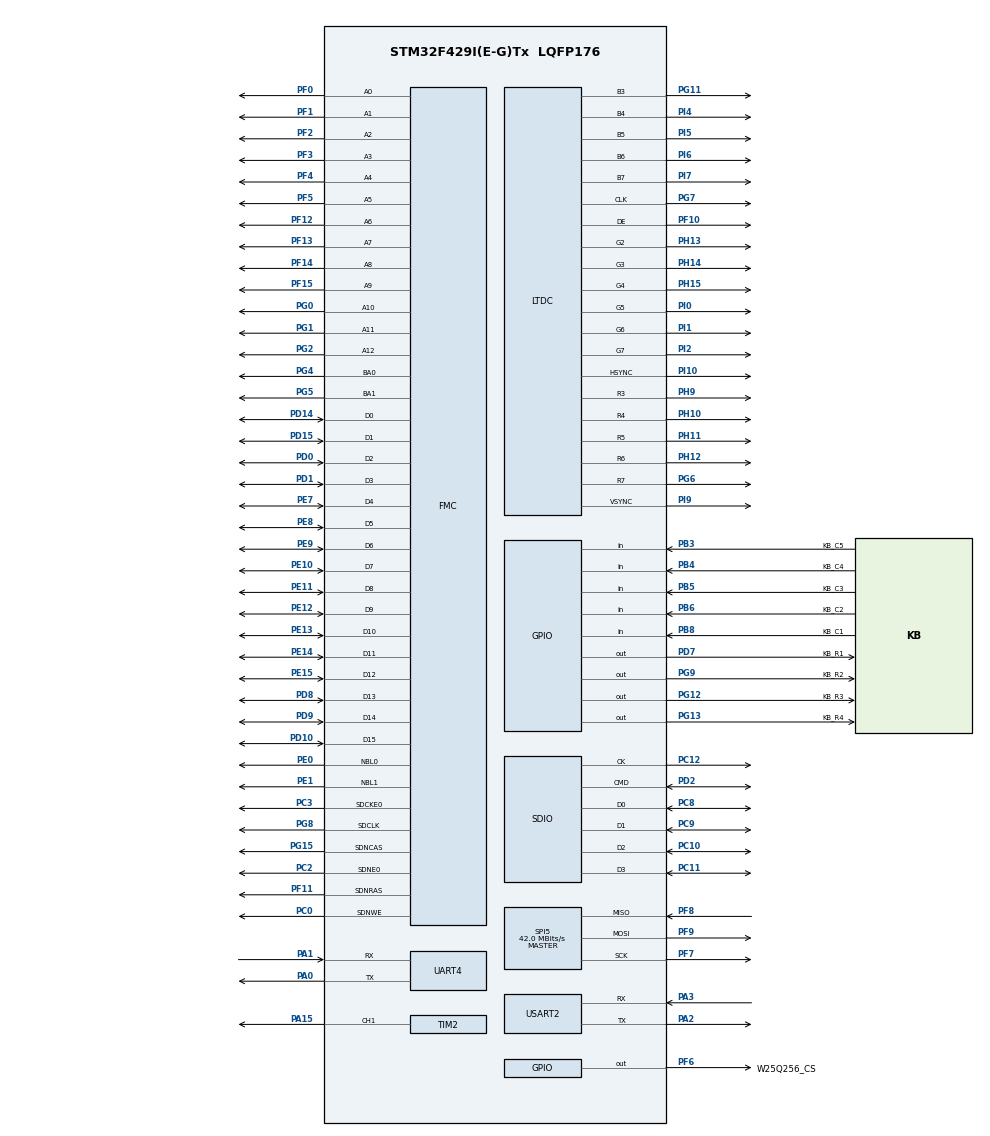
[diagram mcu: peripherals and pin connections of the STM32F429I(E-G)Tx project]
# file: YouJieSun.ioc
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DMA2D.ColorMode=DMA2D_OUTPUT_RGB565
Dma.Request0=UART4_TX
Dma.Request1=UART4_RX
Dma.Request2=USART2_RX
Dma.Request3=USART2_TX
Dma.Request4=SPI5_RX
Dma.Request5=SPI5_TX
Dma.Request6=SDIO_RX
Dma.Request7=SDIO_TX
Dma.SDIO_RX.6.Direction=DMA_PERIPH_TO_MEMORY
Dma.SDIO_RX.6.FIFOMode=DMA_FIFOMODE_ENABLE
Dma.SDIO_RX.6.FIFOThreshold=DMA_FIFO_THRESHOLD_FULL
Dma.SDIO_RX.6.Instance=DMA2_Stream6
Dma.SDIO_RX.6.MemBurst=DMA_MBURST_INC4
Dma.SDIO_RX.6.MemDataAlignment=DMA_MDATAALIGN_WORD
Dma.SDIO_RX.6.MemInc=DMA_MINC_ENABLE
Dma.SDIO_RX.6.Mode=DMA_PFCTRL
Dma.SDIO_RX.6.PeriphBurst=DMA_PBURST_INC4
Dma.SDIO_RX.6.PeriphDataAlignment=DMA_PDATAALIGN_WORD
Dma.SDIO_RX.6.PeriphInc=DMA_PINC_DISABLE
Dma.SDIO_RX.6.Priority=DMA_PRIORITY_LOW
Dma.SDIO_TX.7.Direction=DMA_MEMORY_TO_PERIPH
Dma.SDIO_TX.7.FIFOMode=DMA_FIFOMODE_ENABLE
Dma.SDIO_TX.7.FIFOThreshold=DMA_FIFO_THRESHOLD_FULL
Dma.SDIO_TX.7.Instance=DMA2_Stream3
Dma.SDIO_TX.7.MemBurst=DMA_MBURST_INC4
Dma.SDIO_TX.7.MemDataAlignment=DMA_MDATAALIGN_WORD
Dma.SDIO_TX.7.MemInc=DMA_MINC_ENABLE
Dma.SDIO_TX.7.Mode=DMA_PFCTRL
Dma.SDIO_TX.7.PeriphBurst=DMA_PBURST_INC4
Dma.SDIO_TX.7.PeriphDataAlignment=DMA_PDATAALIGN_WORD
Dma.SDIO_TX.7.PeriphInc=DMA_PINC_DISABLE
Dma.SDIO_TX.7.Priority=DMA_PRIORITY_LOW
Dma.SPI5_RX.4.Direction=DMA_PERIPH_TO_MEMORY
Dma.SPI5_RX.4.FIFOMode=DMA_FIFOMODE_DISABLE
Dma.SPI5_RX.4.Instance=DMA2_Stream5
Dma.SPI5_RX.4.MemDataAlignment=DMA_MDATAALIGN_BYTE
Dma.SPI5_RX.4.MemInc=DMA_MINC_ENABLE
Dma.SPI5_RX.4.Mode=DMA_NORMAL
Dma.SPI5_RX.4.PeriphDataAlignment=DMA_PDATAALIGN_BYTE
Dma.SPI5_RX.4.PeriphInc=DMA_PINC_DISABLE
Dma.SPI5_RX.4.Priority=DMA_PRIORITY_LOW
Dma.SPI5_TX.5.Direction=DMA_MEMORY_TO_PERIPH
Dma.SPI5_TX.5.FIFOMode=DMA_FIFOMODE_DISABLE
Dma.SPI5_TX.5.Instance=DMA2_Stream4
Dma.SPI5_TX.5.MemDataAlignment=DMA_MDATAALIGN_BYTE
Dma.SPI5_TX.5.MemInc=DMA_MINC_ENABLE
Dma.SPI5_TX.5.Mode=DMA_NORMAL
Dma.SPI5_TX.5.PeriphDataAlignment=DMA_PDATAALIGN_BYTE
Dma.SPI5_TX.5.PeriphInc=DMA_PINC_DISABLE
Dma.SPI5_TX.5.Priority=DMA_PRIORITY_LOW
Dma.UART4_RX.1.Direction=DMA_PERIPH_TO_MEMORY
Dma.UART4_RX.1.FIFOMode=DMA_FIFOMODE_DISABLE
Dma.UART4_RX.1.Instance=DMA1_Stream2
Dma.UART4_RX.1.MemDataAlignment=DMA_MDATAALIGN_BYTE
Dma.UART4_RX.1.MemInc=DMA_MINC_ENABLE
Dma.UART4_RX.1.Mode=DMA_NORMAL
Dma.UART4_RX.1.PeriphDataAlignment=DMA_PDATAALIGN_BYTE
Dma.UART4_RX.1.PeriphInc=DMA_PINC_DISABLE
Dma.UART4_RX.1.Priority=DMA_PRIORITY_LOW
Dma.UART4_TX.0.Direction=DMA_MEMORY_TO_PERIPH
Dma.UART4_TX.0.FIFOMode=DMA_FIFOMODE_DISABLE
Dma.UART4_TX.0.Instance=DMA1_Stream4
Dma.UART4_TX.0.MemDataAlignment=DMA_MDATAALIGN_BYTE
Dma.UART4_TX.0.MemInc=DMA_MINC_ENABLE
Dma.UART4_TX.0.Mode=DMA_NORMAL
Dma.UART4_TX.0.PeriphDataAlignment=DMA_PDATAALIGN_BYTE
Dma.UART4_TX.0.PeriphInc=DMA_PINC_DISABLE
Dma.UART4_TX.0.Priority=DMA_PRIORITY_LOW
Dma.USART2_RX.2.Direction=DMA_PERIPH_TO_MEMORY
Dma.USART2_RX.2.FIFOMode=DMA_FIFOMODE_DISABLE
Dma.USART2_RX.2.Instance=DMA1_Stream5
Dma.USART2_RX.2.MemDataAlignment=DMA_MDATAALIGN_BYTE
Dma.USART2_RX.2.MemInc=DMA_MINC_ENABLE
Dma.USART2_RX.2.Mode=DMA_NORMAL
Dma.USART2_RX.2.PeriphDataAlignment=DMA_PDATAALIGN_BYTE
Dma.USART2_RX.2.PeriphInc=DMA_PINC_DISABLE
Dma.USART2_RX.2.Priority=DMA_PRIORITY_LOW
Dma.USART2_TX.3.Direction=DMA_MEMORY_TO_PERIPH
Dma.USART2_TX.3.FIFOMode=DMA_FIFOMODE_DISABLE
Dma.USART2_TX.3.Instance=DMA1_Stream6
Dma.USART2_TX.3.MemDataAlignment=DMA_MDATAALIGN_BYTE
Dma.USART2_TX.3.MemInc=DMA_MINC_ENABLE
Dma.USART2_TX.3.Mode=DMA_NORMAL
Dma.USART2_TX.3.PeriphDataAlignment=DMA_PDATAALIGN_BYTE
Dma.USART2_TX.3.PeriphInc=DMA_PINC_DISABLE
Dma.USART2_TX.3.Priority=DMA_PRIORITY_LOW
FATFS._CODE_PAGE=437
FATFS._USE_LFN=3
FATFS._USE_MUTEX=1
FMC.CASLatency1=FMC_SDRAM_CAS_LATENCY_3
FMC.ColumnBitsNumber1=FMC_SDRAM_COLUMN_BITS_NUM_9
FMC.ExitSelfRefreshDelay1=7
FMC.LoadToActiveDelay1=2
FMC.RCDDelay1=2
FMC.RPDelay1=2
FMC.RPDelay2=2
FMC.ReadBurst1=FMC_SDRAM_RBURST_ENABLE
FMC.ReadBurst2=FMC_SDRAM_RBURST_ENABLE
FMC.ReadPipeDelay1=FMC_SDRAM_RPIPE_DELAY_1
FMC.ReadPipeDelay2=FMC_SDRAM_RPIPE_DELAY_1
FMC.RowCycleDelay1=6
FMC.RowCycleDelay2=6
FMC.SDClockPeriod1=FMC_SDRAM_CLOCK_PERIOD_2
FMC.SDClockPeriod2=FMC_SDRAM_CLOCK_PERIOD_2
FMC.SelfRefreshTime1=6
FMC.WriteRecoveryTime1=4
FREERTOS.BinarySemaphores01=ScreenFlushSemaphore,Dynamic,NULL,Depleted
FREERTOS.Tasks01=UITask,24,2048,StartUITask,As weak,NULL,Dynamic,NULL,NULL;KeyScanTask,25,128,StartKeyScanTask,As weak,NULL,Dynamic,NULL,NULL
FREERTOS.configCHECK_FOR_STACK_OVERFLOW=2
FREERTOS.configGENERATE_RUN_TIME_STATS=1
FREERTOS.configRECORD_STACK_HIGH_ADDRESS=1
FREERTOS.configTOTAL_HEAP_SIZE=32768
FREERTOS.configUSE_MALLOC_FAILED_HOOK=1
FREERTOS.configUSE_TASK_NOTIFICATIONS=1
FREERTOS.configUSE_TICK_HOOK=1
LTDC.ActiveW=800
LTDC.Alpha_L0=255
LTDC.FBStartAdress_L0=0xC0000000
LTDC.HBP=8
LTDC.HFP=8
LTDC.HSync=4
LTDC.ImageHeight_L0=480
LTDC.ImageWidth_L0=800
LTDC.Layers=0
LTDC.PixelFormat_L0=LTDC_PIXEL_FORMAT_RGB565
LTDC.VBP=8
LTDC.VFP=8
LTDC.VSync=2
LTDC.WindowX1_L0=800
LTDC.WindowY1_L0=480
Mcu.Family=STM32F4
Mcu.Name=STM32F429I(E-G)Tx
Mcu.Package=LQFP176
NVIC.DMA1_Stream2_IRQn=true\:5\:0\:false\:false\:true\:true\:false\:true\:true
NVIC.DMA1_Stream4_IRQn=true\:5\:0\:false\:false\:true\:true\:false\:true\:true
NVIC.DMA1_Stream5_IRQn=true\:5\:0\:false\:false\:true\:true\:false\:true\:true
NVIC.DMA1_Stream6_IRQn=true\:5\:0\:false\:false\:true\:true\:false\:true\:true
NVIC.DMA2D_IRQn=true\:7\:0\:true\:false\:true\:true\:true\:true\:true
NVIC.DMA2_Stream3_IRQn=true\:7\:0\:true\:false\:true\:true\:false\:true\:true
NVIC.DMA2_Stream4_IRQn=true\:5\:0\:false\:false\:true\:true\:false\:true\:true
NVIC.DMA2_Stream5_IRQn=true\:5\:0\:false\:false\:true\:false\:false\:true\:true
NVIC.DMA2_Stream6_IRQn=true\:7\:0\:true\:false\:true\:true\:false\:true\:true
NVIC.PriorityGroup=NVIC_PRIORITYGROUP_4
NVIC.SDIO_IRQn=true\:6\:0\:true\:false\:true\:true\:true\:true\:true
NVIC.SPI5_IRQn=true\:5\:0\:false\:false\:true\:true\:true\:true\:true
NVIC.TIM6_DAC_IRQn=true\:15\:0\:false\:false\:true\:false\:false\:true\:true
NVIC.TimeBase=TIM6_DAC_IRQn
NVIC.TimeBaseIP=TIM6
NVIC.UART4_IRQn=true\:6\:0\:true\:false\:true\:true\:false\:true\:true
NVIC.USART2_IRQn=true\:5\:0\:true\:false\:true\:true\:true\:true\:true
PA0/WKUP.Mode=Asynchronous
PA0/WKUP.Signal=UART4_TX
PA1.Mode=Asynchronous
PA1.Signal=UART4_RX
PA13.Mode=Serial_Wire
PA13.Signal=SYS_JTMS-SWDIO
PA14.Mode=Serial_Wire
PA14.Signal=SYS_JTCK-SWCLK
PA15.Signal=S_TIM2_CH1_ETR
PA2.Mode=Asynchronous
PA2.Signal=USART2_TX
PA3.Mode=Asynchronous
PA3.Signal=USART2_RX
PB3.GPIO_Label=KB_C5
PB3.GPIO_PuPd=GPIO_PULLUP
PB3.Signal=GPIO_Input
PB4.GPIO_Label=KB_C4
PB4.GPIO_PuPd=GPIO_PULLUP
PB4.Signal=GPIO_Input
PB5.GPIO_Label=KB_C3
PB5.GPIO_PuPd=GPIO_PULLUP
PB5.Signal=GPIO_Input
PB6.GPIO_Label=KB_C2
PB6.GPIO_PuPd=GPIO_PULLUP
PB6.Signal=GPIO_Input
PB8.GPIO_Label=KB_C1
PB8.GPIO_PuPd=GPIO_PULLUP
PB8.Signal=GPIO_Input
PC0.Signal=FMC_SDNWE
PC10.Mode=SD_4_bits_Wide_bus
PC10.Signal=SDIO_D2
PC11.Mode=SD_4_bits_Wide_bus
PC11.Signal=SDIO_D3
PC12.Mode=SD_4_bits_Wide_bus
PC12.Signal=SDIO_CK
PC14/OSC32_IN.Mode=LSE-External-Oscillator
PC14/OSC32_IN.Signal=RCC_OSC32_IN
PC15/OSC32_OUT.Mode=LSE-External-Oscillator
PC15/OSC32_OUT.Signal=RCC_OSC32_OUT
PC2.Mode=SdramChipSelect1_1
PC2.Signal=FMC_SDNE0
PC3.Mode=SdramChipSelect1_1
PC3.Signal=FMC_SDCKE0
PC8.Mode=SD_4_bits_Wide_bus
PC8.Signal=SDIO_D0
PC9.Mode=SD_4_bits_Wide_bus
PC9.Signal=SDIO_D1
PD0.Signal=FMC_D2_DA2
PD1.Signal=FMC_D3_DA3
PD10.Signal=FMC_D15_DA15
PD14.Signal=FMC_D0_DA0
PD15.Signal=FMC_D1_DA1
PD2.Mode=SD_4_bits_Wide_bus
PD2.Signal=SDIO_CMD
PD7.GPIO_Label=KB_R1
PD7.GPIO_Speed=GPIO_SPEED_FREQ_VERY_HIGH
PD7.PinState=GPIO_PIN_SET
PD7.Signal=GPIO_Output
PD8.Signal=FMC_D13_DA13
PD9.Signal=FMC_D14_DA14
PE0.Signal=FMC_NBL0
PE1.Signal=FMC_NBL1
PE10.Signal=FMC_D7_DA7
PE11.Signal=FMC_D8_DA8
PE12.Signal=FMC_D9_DA9
PE13.Signal=FMC_D10_DA10
PE14.Signal=FMC_D11_DA11
PE15.Signal=FMC_D12_DA12
PE7.Signal=FMC_D4_DA4
PE8.Signal=FMC_D5_DA5
PE9.Signal=FMC_D6_DA6
PF0.Signal=FMC_A0
PF1.Signal=FMC_A1
PF10.GPIO_Speed=GPIO_SPEED_FREQ_VERY_HIGH
PF10.Mode=RGB565
PF10.Signal=LTDC_DE
PF11.Signal=FMC_SDNRAS
PF12.Signal=FMC_A6
PF13.Signal=FMC_A7
PF14.Signal=FMC_A8
PF15.Signal=FMC_A9
PF2.Signal=FMC_A2
PF3.Signal=FMC_A3
PF4.Signal=FMC_A4
PF5.Signal=FMC_A5
PF6.GPIO_Label=W25Q256_CS
PF6.GPIO_Speed=GPIO_SPEED_FREQ_VERY_HIGH
PF6.PinState=GPIO_PIN_SET
PF6.Signal=GPIO_Output
PF7.Mode=Full_Duplex_Master
PF7.Signal=SPI5_SCK
PF8.Mode=Full_Duplex_Master
PF8.Signal=SPI5_MISO
PF9.Mode=Full_Duplex_Master
PF9.Signal=SPI5_MOSI
PG0.Signal=FMC_A10
PG1.Signal=FMC_A11
PG11.GPIO_Speed=GPIO_SPEED_FREQ_VERY_HIGH
PG11.Mode=RGB565
PG11.Signal=LTDC_B3
PG12.GPIO_Label=KB_R3
PG12.GPIO_Speed=GPIO_SPEED_FREQ_VERY_HIGH
PG12.PinState=GPIO_PIN_SET
PG12.Signal=GPIO_Output
PG13.GPIO_Label=KB_R4
PG13.GPIO_Speed=GPIO_SPEED_FREQ_VERY_HIGH
PG13.PinState=GPIO_PIN_SET
PG13.Signal=GPIO_Output
PG15.Signal=FMC_SDNCAS
PG2.Signal=FMC_A12
PG4.Signal=FMC_A14_BA0
PG5.Signal=FMC_A15_BA1
PG6.GPIO_Speed=GPIO_SPEED_FREQ_VERY_HIGH
PG6.Mode=RGB565
PG6.Signal=LTDC_R7
PG7.GPIO_Speed=GPIO_SPEED_FREQ_VERY_HIGH
PG7.Mode=RGB565
PG7.Signal=LTDC_CLK
PG8.Signal=FMC_SDCLK
PG9.GPIO_Label=KB_R2
PG9.GPIO_Speed=GPIO_SPEED_FREQ_VERY_HIGH
PG9.PinState=GPIO_PIN_SET
PG9.Signal=GPIO_Output
PH0/OSC_IN.Mode=HSE-External-Oscillator
PH0/OSC_IN.Signal=RCC_OSC_IN
PH1/OSC_OUT.Mode=HSE-External-Oscillator
PH1/OSC_OUT.Signal=RCC_OSC_OUT
PH10.GPIO_Speed=GPIO_SPEED_FREQ_VERY_HIGH
PH10.Mode=RGB565
PH10.Signal=LTDC_R4
PH11.GPIO_Speed=GPIO_SPEED_FREQ_VERY_HIGH
PH11.Mode=RGB565
PH11.Signal=LTDC_R5
PH12.GPIO_Speed=GPIO_SPEED_FREQ_VERY_HIGH
PH12.Mode=RGB565
PH12.Signal=LTDC_R6
PH13.GPIO_Speed=GPIO_SPEED_FREQ_VERY_HIGH
PH13.Mode=RGB565
PH13.Signal=LTDC_G2
PH14.GPIO_Speed=GPIO_SPEED_FREQ_VERY_HIGH
PH14.Mode=RGB565
PH14.Signal=LTDC_G3
PH15.GPIO_Speed=GPIO_SPEED_FREQ_VERY_HIGH
PH15.Mode=RGB565
PH15.Signal=LTDC_G4
PH9.GPIO_Speed=GPIO_SPEED_FREQ_VERY_HIGH
PH9.Mode=RGB565
PH9.Signal=LTDC_R3
PI0.GPIO_Speed=GPIO_SPEED_FREQ_VERY_HIGH
PI0.Mode=RGB565
PI0.Signal=LTDC_G5
PI1.GPIO_Speed=GPIO_SPEED_FREQ_VERY_HIGH
PI1.Mode=RGB565
PI1.Signal=LTDC_G6
PI10.GPIO_Speed=GPIO_SPEED_FREQ_VERY_HIGH
PI10.Mode=RGB565
PI10.Signal=LTDC_HSYNC
PI2.GPIO_Speed=GPIO_SPEED_FREQ_VERY_HIGH
PI2.Mode=RGB565
PI2.Signal=LTDC_G7
PI4.GPIO_Speed=GPIO_SPEED_FREQ_VERY_HIGH
PI4.Mode=RGB565
PI4.Signal=LTDC_B4
PI5.GPIO_Speed=GPIO_SPEED_FREQ_VERY_HIGH
PI5.Mode=RGB565
PI5.Signal=LTDC_B5
PI6.GPIO_Speed=GPIO_SPEED_FREQ_VERY_HIGH
PI6.Mode=RGB565
PI6.Signal=LTDC_B6
PI7.GPIO_Speed=GPIO_SPEED_FREQ_VERY_HIGH
PI7.Mode=RGB565
PI7.Signal=LTDC_B7
PI9.GPIO_Speed=GPIO_SPEED_FREQ_VERY_HIGH
PI9.Mode=RGB565
PI9.Signal=LTDC_VSYNC
ProjectManager.HeapSize=0x2000
ProjectManager.StackSize=0x2000
ProjectManager.TargetToolchain=CMake
RCC.48MHZClocksFreq_Value=48000000
RCC.AHBFreq_Value=168000000
RCC.APB1CLKDivider=RCC_HCLK_DIV4
RCC.APB1Freq_Value=42000000
RCC.APB1TimFreq_Value=84000000
RCC.APB2CLKDivider=RCC_HCLK_DIV2
RCC.APB2Freq_Value=84000000
RCC.APB2TimFreq_Value=168000000
RCC.CortexFreq_Value=168000000
RCC.HCLKFreq_Value=168000000
RCC.HSE_VALUE=25000000
RCC.HSI_VALUE=16000000
RCC.PLLM=25
RCC.PLLN=336
RCC.PLLQ=7
RCC.PLLSAIN=132
RCC.PLLSourceVirtual=RCC_PLLSOURCE_HSE
RCC.RCC_RTC_Clock_Source=RCC_RTCCLKSOURCE_LSE
RCC.RCC_RTC_Clock_SourceVirtual=RCC_RTCCLKSOURCE_LSE
RCC.SYSCLKFreq_VALUE=168000000
RCC.SYSCLKSource=RCC_SYSCLKSOURCE_PLLCLK
RCC.VCOOutputFreq_Value=336000000
RTC.Hours=4
RTC.Month=RTC_MONTH_JULY
RTC.Year=26
SH.FMC_A0.0=FMC_A0,13b-sda1
SH.FMC_A1.0=FMC_A1,13b-sda1
SH.FMC_A10.0=FMC_A10,13b-sda1
SH.FMC_A11.0=FMC_A11,13b-sda1
SH.FMC_A12.0=FMC_A12,13b-sda1
SH.FMC_A14_BA0.0=FMC_BA0,FourSdramBanks1
SH.FMC_A15_BA1.0=FMC_BA1,FourSdramBanks1
SH.FMC_A2.0=FMC_A2,13b-sda1
SH.FMC_A3.0=FMC_A3,13b-sda1
SH.FMC_A4.0=FMC_A4,13b-sda1
SH.FMC_A5.0=FMC_A5,13b-sda1
SH.FMC_A6.0=FMC_A6,13b-sda1
SH.FMC_A7.0=FMC_A7,13b-sda1
SH.FMC_A8.0=FMC_A8,13b-sda1
SH.FMC_A9.0=FMC_A9,13b-sda1
SH.FMC_D0_DA0.0=FMC_D0,sd-16b-d1
SH.FMC_D10_DA10.0=FMC_D10,sd-16b-d1
SH.FMC_D11_DA11.0=FMC_D11,sd-16b-d1
SH.FMC_D12_DA12.0=FMC_D12,sd-16b-d1
SH.FMC_D13_DA13.0=FMC_D13,sd-16b-d1
SH.FMC_D14_DA14.0=FMC_D14,sd-16b-d1
SH.FMC_D15_DA15.0=FMC_D15,sd-16b-d1
SH.FMC_D1_DA1.0=FMC_D1,sd-16b-d1
SH.FMC_D2_DA2.0=FMC_D2,sd-16b-d1
SH.FMC_D3_DA3.0=FMC_D3,sd-16b-d1
SH.FMC_D4_DA4.0=FMC_D4,sd-16b-d1
SH.FMC_D5_DA5.0=FMC_D5,sd-16b-d1
SH.FMC_D6_DA6.0=FMC_D6,sd-16b-d1
SH.FMC_D7_DA7.0=FMC_D7,sd-16b-d1
SH.FMC_D8_DA8.0=FMC_D8,sd-16b-d1
SH.FMC_D9_DA9.0=FMC_D9,sd-16b-d1
SH.FMC_NBL0.0=FMC_NBL0,Sd2ByteEnable1
SH.FMC_NBL1.0=FMC_NBL1,Sd2ByteEnable1
SH.FMC_SDCLK.0=FMC_SDCLK,13b-sda1
SH.FMC_SDNCAS.0=FMC_SDNCAS,13b-sda1
SH.FMC_SDNRAS.0=FMC_SDNRAS,13b-sda1
SH.FMC_SDNWE.0=FMC_SDNWE,13b-sda1
SH.S_TIM2_CH1_ETR.0=TIM2_CH1,PWM Generation1 CH1
SPI5.CalculateBaudRate=42.0 MBits/s
SPI5.Direction=SPI_DIRECTION_2LINES
SPI5.Mode=SPI_MODE_MASTER
SPI5.VirtualType=VM_MASTER
TIM2.Channel-PWM\ Generation1\ CH1=TIM_CHANNEL_1
TIM2.Period=99
TIM2.Prescaler=839
UART4.VirtualMode=Asynchronous
USART2.VirtualMode=VM_ASYNC
VP_DMA2D_VS_DMA2D.Mode=DMA2D_Activate
VP_FATFS_VS_SDIO.Mode=SDIO
VP_FREERTOS_VS_CMSIS_V2.Mode=CMSIS_V2
VP_RTC_VS_RTC_Activate.Mode=RTC_Enabled
VP_RTC_VS_RTC_Calendar.Mode=RTC_Calendar
VP_SYS_VS_tim6.Mode=TIM6
board=custom

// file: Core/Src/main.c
/* USER CODE BEGIN Header */
/**
  ******************************************************************************
  * @file           : main.c
  * @brief          : Main program body
  ******************************************************************************
  * @attention
  *
  * Copyright (c) 2026 STMicroelectronics.
  * All rights reserved.
  *
  * This software is licensed under terms that can be found in the LICENSE file
  * in the root directory of this software component.
  * If no LICENSE file comes with this software, it is provided AS-IS.
  *
  ******************************************************************************
  */
/* USER CODE END Header */
#include "main.h"
#include "cmsis_os.h"
#include "dma.h"
#include "dma2d.h"
#include "fatfs.h"
#include "ltdc.h"
#include "rtc.h"
#include "sdio.h"
#include "spi.h"
#include "tim.h"
#include "usart.h"
#include "gpio.h"
#include "fmc.h"

/* USER CODE BEGIN PD */
#define APP_START_ADDR      (0x08020000U)
/* USER CODE END PD */

void SystemClock_Config(void);

void MX_FREERTOS_Init(void);

int main(void)
{
    /* USER CODE BEGIN 1 */
    __disable_irq();

    // 重定向中断向量表
    SCB->VTOR = APP_START_ADDR;

    __enable_irq();
    /* USER CODE END 1 */

    /* MCU Configuration--------------------------------------------------------*/

    /* Reset of all peripherals, Initializes the Flash interface and the Systick. */
    HAL_Init();

    /* Configure the system clock */
    SystemClock_Config();

    /* Initialize all configured peripherals */
    MX_GPIO_Init();
    MX_DMA_Init();
    MX_FMC_Init();
    MX_SPI5_Init();
    MX_TIM2_Init();
    MX_UART4_Init();
    MX_USART2_UART_Init();
    MX_DMA2D_Init();
    MX_LTDC_Init();
    MX_RTC_Init();
    MX_SDIO_SD_Init();
    MX_FATFS_Init();
    /* USER CODE BEGIN 2 */
    HAL_TIM_PWM_Start(&htim2, TIM_CHANNEL_1);
    /* USER CODE END 2 */

    /* Init scheduler */
    osKernelInitialize(); /* Call init function for freertos objects (in cmsis_os2.c) */
    MX_FREERTOS_Init();

    /* Start scheduler */
    osKernelStart();

    /* We should never get here as control is now taken by the scheduler */

    /* Infinite loop */
    while (1)
    {

    }
}

void SystemClock_Config(void)
{
    RCC_OscInitTypeDef RCC_OscInitStruct = {0};
    RCC_ClkInitTypeDef RCC_ClkInitStruct = {0};

    /** Configure the main internal regulator output voltage
    */
    __HAL_RCC_PWR_CLK_ENABLE();
    __HAL_PWR_VOLTAGESCALING_CONFIG(PWR_REGULATOR_VOLTAGE_SCALE1);

    /** Initializes the RCC Oscillators according to the specified parameters
    * in the RCC_OscInitTypeDef structure.
    */
    // 先将时钟源选择为内部时钟
    RCC_ClkInitStruct.ClockType = RCC_CLOCKTYPE_SYSCLK;
    RCC_ClkInitStruct.SYSCLKSource = RCC_SYSCLKSOURCE_HSI;
    if (HAL_RCC_ClockConfig(&RCC_ClkInitStruct, FLASH_LATENCY_5) != HAL_OK)
    {
        Error_Handler();
    }

    RCC_OscInitStruct.OscillatorType = RCC_OSCILLATORTYPE_HSE | RCC_OSCILLATORTYPE_LSE;
    RCC_OscInitStruct.HSEState = RCC_HSE_ON;
    RCC_OscInitStruct.LSEState = RCC_LSE_ON;
    RCC_OscInitStruct.PLL.PLLState = RCC_PLL_ON;
    RCC_OscInitStruct.PLL.PLLSource = RCC_PLLSOURCE_HSE;
    RCC_OscInitStruct.PLL.PLLM = 25;
    RCC_OscInitStruct.PLL.PLLN = 336;
    RCC_OscInitStruct.PLL.PLLP = RCC_PLLP_DIV2;
    RCC_OscInitStruct.PLL.PLLQ = 7;
    if (HAL_RCC_OscConfig(&RCC_OscInitStruct) != HAL_OK)
    {
        Error_Handler();
    }

    /** Initializes the CPU, AHB and APB buses clocks
    */
    RCC_ClkInitStruct.ClockType = RCC_CLOCKTYPE_HCLK | RCC_CLOCKTYPE_SYSCLK
                                  | RCC_CLOCKTYPE_PCLK1 | RCC_CLOCKTYPE_PCLK2;
    RCC_ClkInitStruct.SYSCLKSource = RCC_SYSCLKSOURCE_PLLCLK;
    RCC_ClkInitStruct.AHBCLKDivider = RCC_SYSCLK_DIV1;
    RCC_ClkInitStruct.APB1CLKDivider = RCC_HCLK_DIV4;
    RCC_ClkInitStruct.APB2CLKDivider = RCC_HCLK_DIV2;

    if (HAL_RCC_ClockConfig(&RCC_ClkInitStruct, FLASH_LATENCY_5) != HAL_OK)
    {
        Error_Handler();
    }
}

void HAL_TIM_PeriodElapsedCallback(TIM_HandleTypeDef *htim)
{
    if (htim->Instance == TIM6)
    {
        HAL_IncTick();
    }
}

void Error_Handler(void)
{
    __disable_irq();
    while (1)
    {
    }
}

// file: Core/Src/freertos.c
/* USER CODE BEGIN Header */
/**
  ******************************************************************************
  * File Name          : freertos.c
  * Description        : Code for freertos applications
  ******************************************************************************
  * @attention
  *
  * Copyright (c) 2026 STMicroelectronics.
  * All rights reserved.
  *
  * This software is licensed under terms that can be found in the LICENSE file
  * in the root directory of this software component.
  * If no LICENSE file comes with this software, it is provided AS-IS.
  *
  ******************************************************************************
  */
/* USER CODE END Header */

#include "FreeRTOS.h"
#include "task.h"
#include "main.h"
#include "cmsis_os.h"

/* USER CODE BEGIN Includes */
#include "timers.h"
#include "fpga_comm.h"
#include "test_task.h"
#include "ui_task.h"
/* USER CODE END Includes */

/* USER CODE BEGIN PD */
#define TEST_TASK_STACK_SIZE (256)
#define TEST_TASK_PRIORITY (osPriorityNormal4)

#define COMMUNICATE_TASK_STACK_SIZE (256)
#define COMMUNICATE_TASK_PRIORITY (osPriorityAboveNormal)

#define FATFS_TASK_STACK_SIZE (1024)
#define FATFS_TASK_PRIORITY (osPriorityNormal1)

#define INIT_TASK_STACK_SIZE (256)
#define INIT_TASK_PRIORITY (osPriorityHigh)

#define TEST_EVENT_QUEUE_LENGTH     (10U)
#define FPGA_REQUEST_QUEUE_LENGTH   (16U)
#define UI_EVENT_QUEUE_LENGTH       (1U)
/* USER CODE END PD */

/* USER CODE BEGIN Variables */
/*
 * 任务句柄
 */
TaskHandle_t communicate_taskHandle = NULL;
TaskHandle_t test_taskHandle = NULL;
TaskHandle_t fatfs_taskHandle = NULL;
TaskHandle_t init_taskHandle = NULL;

TimerHandle_t fpga_communication_timer = NULL;

/*
 * 信号量句柄句柄
 */
/* SPI5发送完成信号量 */
SemaphoreHandle_t spi5_tx_semaphore = NULL;
/* SPI5接收完成信号量 */
SemaphoreHandle_t spi5_rx_semaphore = NULL;
/* SPI5发送并接收信号量 */
SemaphoreHandle_t spi5_tx_rx_semaphore = NULL;

/* ----------------------------队列句柄------------------------------------ */
/* FPGA 串口读取指令 发送队列 */
QueueHandle_t test_event_queue = NULL;
QueueHandle_t fpga_request_queue = NULL;
QueueHandle_t ui_event_queue = NULL;
/* USER CODE END Variables */
/* Definitions for UITask */
osThreadId_t UITaskHandle;
const osThreadAttr_t UITask_attributes = {
    .name = "UITask",
    .stack_size = 2048 * 4,
    .priority = (osPriority_t) osPriorityNormal,
};
/* Definitions for KeyScanTask */
osThreadId_t KeyScanTaskHandle;
const osThreadAttr_t KeyScanTask_attributes = {
    .name = "KeyScanTask",
    .stack_size = 128 * 4,
    .priority = (osPriority_t) osPriorityNormal1,
};
/* Definitions for ScreenFlushSemaphore */
osSemaphoreId_t ScreenFlushSemaphoreHandle;
const osSemaphoreAttr_t ScreenFlushSemaphore_attributes = {
    .name = "ScreenFlushSemaphore"
};

/* USER CODE BEGIN FunctionPrototypes */
void start_test_task(void *argument);

void fpga_communication_timer_cb(TimerHandle_t xTimer);

void start_communicate_task(void *argument);

void start_fatfs_task(void *argument);

void start_init_task(void *argument);

/* USER CODE END FunctionPrototypes */

void StartUITask(void *argument);

void StartKeyScanTask(void *argument);

void MX_FREERTOS_Init(void); /* (MISRA C 2004 rule 8.1) */

/* Hook prototypes */
void configureTimerForRunTimeStats(void);

unsigned long getRunTimeCounterValue(void);

void vApplicationTickHook(void);

void vApplicationStackOverflowHook(xTaskHandle xTask, signed char *pcTaskName);

void vApplicationMallocFailedHook(void);

/* USER CODE BEGIN 1 */
/* Functions needed when configGENERATE_RUN_TIME_STATS is on */
__weak void configureTimerForRunTimeStats(void)
{
}

__weak unsigned long getRunTimeCounterValue(void)
{
    return 0;
}

/* USER CODE END 1 */

/* USER CODE BEGIN 3 */
void vApplicationTickHook(void)
{
    /* This function will be called by each tick interrupt if
    configUSE_TICK_HOOK is set to 1 in FreeRTOSConfig.h. User code can be
    added here, but the tick hook is called from an interrupt context, so
    code must not attempt to block, and only the interrupt safe FreeRTOS API
    functions can be used (those that end in FromISR()). */
}

/* USER CODE END 3 */

/* USER CODE BEGIN 4 */
void vApplicationStackOverflowHook(xTaskHandle xTask, signed char *pcTaskName)
{
    /* Run time stack overflow checking is performed if
    configCHECK_FOR_STACK_OVERFLOW is defined to 1 or 2. This hook function is
    called if a stack overflow is detected. */
}

/* USER CODE END 4 */

/* USER CODE BEGIN 5 */
void vApplicationMallocFailedHook(void)
{
    /* vApplicationMallocFailedHook() will only be called if
    configUSE_MALLOC_FAILED_HOOK is set to 1 in FreeRTOSConfig.h. It is a hook
    function that will get called if a call to pvPortMalloc() fails.
    pvPortMalloc() is called internally by the kernel whenever a task, queue,
    timer or semaphore is created. It is also called by various parts of the
    demo application. If heap_1.c or heap_2.c are used, then the size of the
    heap available to pvPortMalloc() is defined by configTOTAL_HEAP_SIZE in
    FreeRTOSConfig.h, and the xPortGetFreeHeapSize() API function can be used
    to query the size of free heap space that remains (although it does not
    provide information on how the remaining heap might be fragmented). */
}

/* USER CODE END 5 */

void MX_FREERTOS_Init(void)
{

    /* Create the semaphores(s) */
    /* creation of ScreenFlushSemaphore */
    ScreenFlushSemaphoreHandle = osSemaphoreNew(1, 0, &ScreenFlushSemaphore_attributes);

    /* USER CODE BEGIN RTOS_SEMAPHORES */
    /* add semaphores, ... */
    spi5_tx_semaphore = xSemaphoreCreateBinary();
    if (spi5_tx_semaphore != NULL)
    {
        vQueueAddToRegistry(spi5_tx_semaphore, "SPI5_TX_Semaphore");
    }
    spi5_rx_semaphore = xSemaphoreCreateBinary();
    spi5_tx_rx_semaphore = xSemaphoreCreateBinary();
    /* USER CODE END RTOS_SEMAPHORES */

    /* USER CODE BEGIN RTOS_TIMERS */
    /* start timers, add new ones, ... */
    fpga_communication_timer = xTimerCreate("fpga_communication_timer", pdMS_TO_TICKS(1000U),pdTRUE, NULL,
                                            fpga_communication_timer_cb);
    /* USER CODE END RTOS_TIMERS */

    /* USER CODE BEGIN RTOS_QUEUES */
    /* add queues, ... */
    test_event_queue = xQueueCreate(TEST_EVENT_QUEUE_LENGTH, sizeof(test_event_t));
    if (test_event_queue != NULL)
    {
        vQueueAddToRegistry(test_event_queue, "TEST_EVENT_QUEUE");
    }
    fpga_request_queue = xQueueCreate(FPGA_REQUEST_QUEUE_LENGTH, sizeof(fpga_request_t));
    if (fpga_request_queue != NULL)
    {
        vQueueAddToRegistry(fpga_request_queue, "FPGA_REQUEST_QUEUE");
    }
    ui_event_queue = xQueueCreate(UI_EVENT_QUEUE_LENGTH, sizeof(ui_event_t));
    if (ui_event_queue != NULL)
    {
        vQueueAddToRegistry(ui_event_queue, "UI_EVENT_QUEUE");
    }
    /* USER CODE END RTOS_QUEUES */

    /* Create the thread(s) */
    /* creation of UITask */
    UITaskHandle = osThreadNew(StartUITask, NULL, &UITask_attributes);

    /* creation of KeyScanTask */
    KeyScanTaskHandle = osThreadNew(StartKeyScanTask, NULL, &KeyScanTask_attributes);

    /* USER CODE BEGIN RTOS_THREADS */
    /* add threads, ... */
    xTaskCreate(start_communicate_task, "CommunicateTask",COMMUNICATE_TASK_STACK_SIZE, NULL, COMMUNICATE_TASK_PRIORITY,
                &communicate_taskHandle);
    xTaskCreate(start_test_task, "TestTask", TEST_TASK_STACK_SIZE, NULL, TEST_TASK_PRIORITY, &test_taskHandle);
    xTaskCreate(start_fatfs_task, "FATFS_Task", FATFS_TASK_STACK_SIZE, NULL, FATFS_TASK_PRIORITY, &fatfs_taskHandle);
    xTaskCreate(start_init_task, "Init_Task",INIT_TASK_STACK_SIZE,NULL,INIT_TASK_PRIORITY, &init_taskHandle);
    /* USER CODE END RTOS_THREADS */

}

__weak void StartUITask(void *argument)
{
    for (;;)
    {
        osDelay(1);
    }
}

__weak void StartKeyScanTask(void *argument)
{
    for (;;)
    {
        osDelay(1);
    }
}

/* USER CODE BEGIN Application */
__weak void start_test_task(void *argument)
{
    for (;;)
    {
        vTaskDelay(1);
    }
}

__weak void fpga_communication_timer_cb(TimerHandle_t xTimer)
{
}

__weak void start_communicate_task(void *argument)
{
    for (;;)
    {
        vTaskDelay(1);
    }
}

__weak void start_fatfs_task(void *argument)
{
    for (;;)
    {
        vTaskDelay(1);
    }
}

__weak void start_init_task(void *argument)
{
    for (;;)
    {
        vTaskDelay(1);
    }
}

/* USER CODE END Application */
